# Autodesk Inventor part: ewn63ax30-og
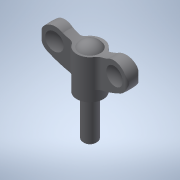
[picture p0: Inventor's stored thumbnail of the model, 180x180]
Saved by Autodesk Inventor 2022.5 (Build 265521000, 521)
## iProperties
Created: 2017-05
Part Number: ewn63ax30-og
Material: 一般
Document SubType Name: Modeling
Designer: imaocorp
Density: 1 g/cm^3
Appearance: 既定
Author: imaocorp
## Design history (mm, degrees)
node "ewn63ax30-og.x_t1"
node "ewn63ax30-og"
node "Base1"
